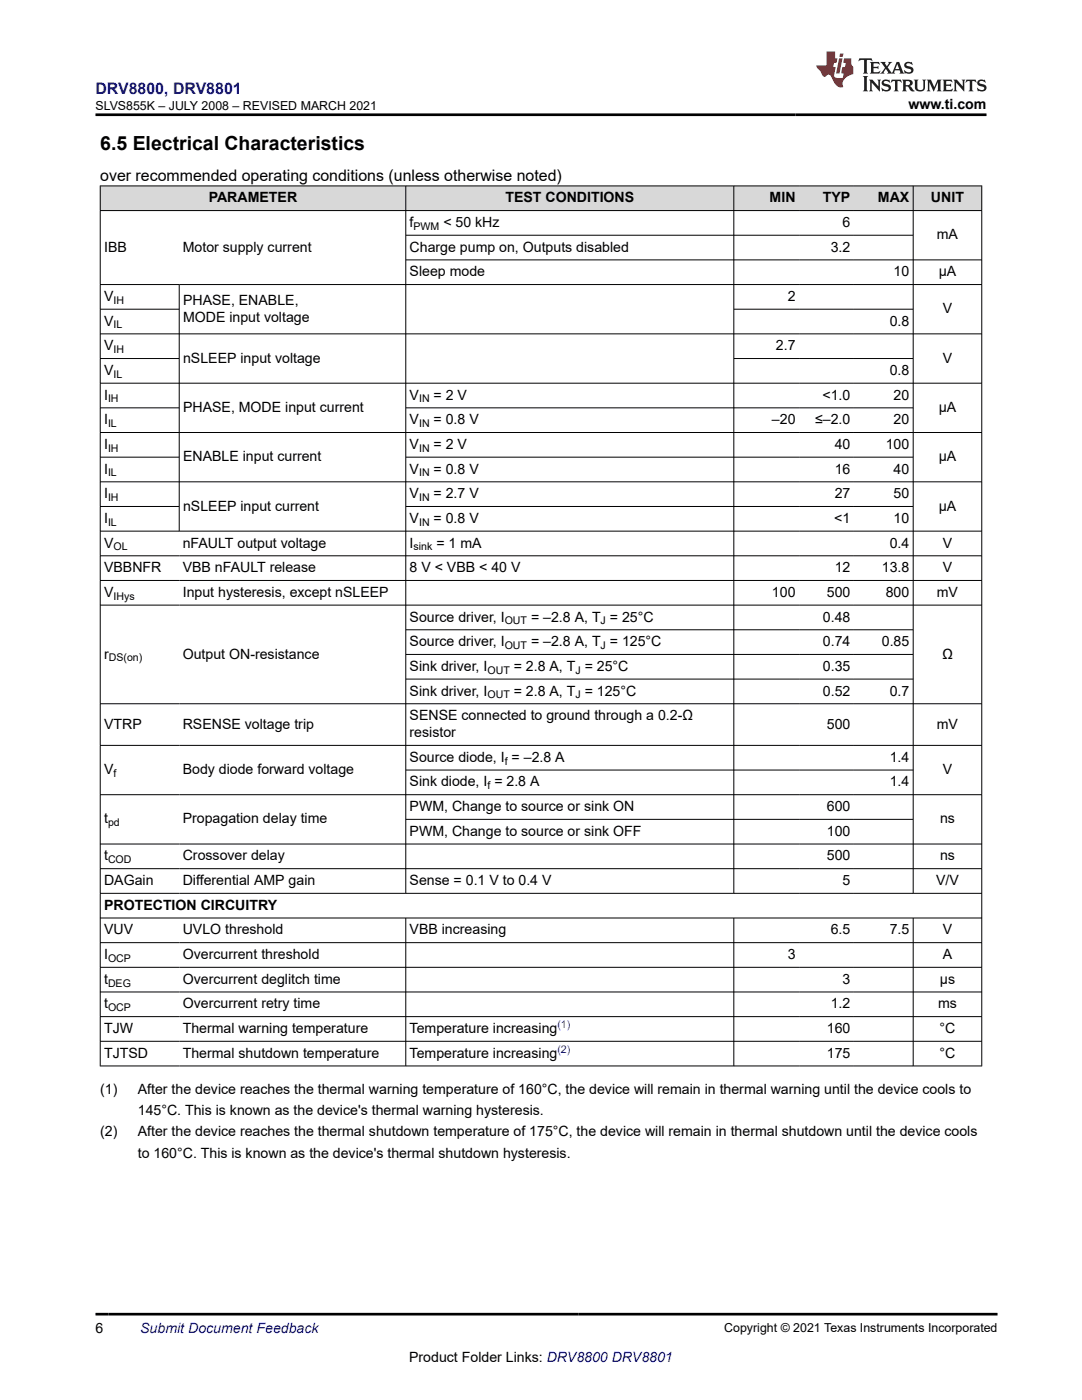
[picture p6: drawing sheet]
<svg xmlns="http://www.w3.org/2000/svg" width="216mm" height="279mm" viewBox="0 0 216 279" stroke-linecap="round" stroke-linejoin="round" font-family="sans-serif">
<defs><g id="words">
<text font-size="3.9" x="20" y="29.9">6.5 Electrical Characteristics</text>
<text font-size="3.2" fill="#00f" x="19.1" y="18.7">DRV8800, DRV8801</text>
<text font-size="3.2" x="20" y="36.1">over recommended operating conditions (unless otherwise noted)</text>
<g font-size="2.8">
<text x="181.3" y="21.8">www.ti.com</text>
<text x="41.7" y="40.4">PARAMETER</text>
<text x="100.8" y="40.4">TEST CONDITIONS</text>
<text x="153.6" y="40.4">MIN</text>
<text x="164.2" y="40.4">TYP</text>
<text x="175.2" y="40.4">MAX</text>
<text x="185.8" y="40.4">UNIT</text>
<text x="81.7" y="45.3">f</text>
<text x="88.5" y="45.3">&lt; 50 kHz</text>
<text x="168.1" y="45.3">6</text>
<text x="186.9" y="47.8">mA</text>
<text x="20.8" y="50.2">IBB</text>
<text x="36.5" y="50.2">Motor supply current</text>
<text x="81.7" y="50.2">Charge pump on, Outputs disabled</text>
<text x="165.8" y="50.2">3.2</text>
<text x="81.7" y="55.1">Sleep mode</text>
<text x="178.3" y="55.1">10</text>
<text x="187.3" y="55.1">μA</text>
<text x="20.8" y="65">V</text>
<text x="20.8" y="60.1">V</text>
<text x="36.5" y="60.8">PHASE, ENABLE,</text>
<text x="36.5" y="64.2">MODE input voltage</text>
<text x="157.2" y="60.1">2</text>
<text x="177.5" y="65">0.8</text>
<text x="188.1" y="62.5">V</text>
<text x="20.8" y="69.9">V</text>
<text x="154.8" y="69.9">2.7</text>
<text x="20.8" y="74.8">V</text>
<text x="36.5" y="72.4">nSLEEP input voltage</text>
<text x="177.5" y="74.8">0.8</text>
<text x="188.1" y="72.4">V</text>
<text x="20.8" y="79.7">I</text>
<text x="36.5" y="82.2">PHASE, MODE input current</text>
<text x="81.7" y="79.7">V</text>
<text x="86.5" y="79.7">= 2 V</text>
<text x="164.1" y="79.7">&lt;1.0</text>
<text x="178.3" y="79.7">20</text>
<text x="187.3" y="82.2">μA</text>
<text x="20.8" y="84.7">I</text>
<text x="20.8" y="89.6">I</text>
<text x="81.7" y="84.7">V</text>
<text x="81.7" y="89.6">V</text>
<text x="86.5" y="89.6">= 2 V</text>
<text x="86.5" y="84.7">= 0.8 V</text>
<text x="154" y="84.7">–20</text>
<text x="162.6" y="84.7">≤–2.0</text>
<text x="166.6" y="89.6">40</text>
<text x="176.7" y="89.6">100</text>
<text x="178.3" y="84.7">20</text>
<text x="20.8" y="94.5">I</text>
<text x="36.5" y="92.1">ENABLE input current</text>
<text x="81.7" y="94.5">V</text>
<text x="86.5" y="94.5">= 0.8 V</text>
<text x="166.6" y="94.5">16</text>
<text x="178.3" y="94.5">40</text>
<text x="187.3" y="92.1">μA</text>
<text x="20.8" y="99.4">I</text>
<text x="36.5" y="101.9">nSLEEP input current</text>
<text x="81.7" y="99.4">V</text>
<text x="86.5" y="99.4">= 2.7 V</text>
<text x="166.6" y="99.4">27</text>
<text x="178.3" y="99.4">50</text>
<text x="187.3" y="101.9">μA</text>
<text x="20.8" y="104.4">I</text>
<text x="81.7" y="104.4">V</text>
<text x="86.5" y="104.4">= 0.8 V</text>
<text x="166.5" y="104.4">&lt;1</text>
<text x="178.3" y="104.4">10</text>
<text x="20.8" y="109.3">V</text>
<text x="36.5" y="109.3">nFAULT output voltage</text>
<text x="81.7" y="109.3">I</text>
<text x="87.1" y="109.3">= 1 mA</text>
<text x="177.5" y="109.3">0.4</text>
<text x="188.1" y="109.3">V</text>
<text x="20.8" y="114.2">VBBNFR</text>
<text x="20.8" y="119.1">V</text>
<text x="36.5" y="114.2">VBB nFAULT release</text>
<text x="36.5" y="119.1">Input hysteresis, except nSLEEP</text>
<text x="81.7" y="114.2">8 V &lt; VBB &lt; 40 V</text>
<text x="154" y="119.1">100</text>
<text x="165" y="119.1">500</text>
<text x="166.6" y="114.2">12</text>
<text x="176" y="114.2">13.8</text>
<text x="176.7" y="119.1">800</text>
<text x="186.9" y="119.1">mV</text>
<text x="188.1" y="114.2">V</text>
<text x="81.7" y="124">Source driver, I</text>
<text x="106" y="124">= –2.8 A, T = 25°C</text>
<text x="164.2" y="124">0.48</text>
<text x="20.8" y="131.4">r</text>
<text x="36.5" y="131.4">Output ON-resistance</text>
<text x="81.7" y="129">Source driver, I</text>
<text x="106" y="129">= –2.8 A, T = 125°C</text>
<text x="164.2" y="129">0.74</text>
<text x="176" y="129">0.85</text>
<text x="188" y="131.4">Ω</text>
<text x="81.7" y="133.9">Sink driver, I</text>
<text x="102.5" y="133.9">= 2.8 A, T = 25°C</text>
<text x="164.2" y="133.9">0.35</text>
<text x="81.7" y="138.8">Sink driver, I</text>
<text x="81.7" y="143.7">SENSE connected to ground through a 0.2-Ω</text>
<text x="102.5" y="138.8">= 2.8 A, T = 125°C</text>
<text x="164.2" y="138.8">0.52</text>
<text x="177.5" y="138.8">0.7</text>
<text x="20.8" y="145.4">VTRP</text>
<text x="36.5" y="145.4">RSENSE voltage trip</text>
<text x="81.7" y="147.1">resistor</text>
<text x="165" y="145.4">500</text>
<text x="186.9" y="145.4">mV</text>
<text x="20.8" y="154.5">V</text>
<text x="36.5" y="154.5">Body diode forward voltage</text>
<text x="81.7" y="152">Source diode, I = –2.8 A</text>
<text x="177.5" y="152">1.4</text>
<text x="188.1" y="154.5">V</text>
<text x="81.7" y="161.9">PWM, Change to source or sink ON</text>
<text x="81.7" y="157">Sink diode, I = 2.8 A</text>
<text x="165" y="161.9">600</text>
<text x="177.5" y="157">1.4</text>
<text x="20.8" y="164.3">t</text>
<text x="36.5" y="164.3">Propagation delay time</text>
<text x="81.7" y="166.8">PWM, Change to source or sink OFF</text>
<text x="165" y="166.8">100</text>
<text x="187.6" y="164.3">ns</text>
<text x="20.8" y="171.7">t</text>
<text x="36.5" y="171.7">Crossover delay</text>
<text x="165" y="171.7">500</text>
<text x="187.6" y="171.7">ns</text>
<text x="20.8" y="176.6">DAGain</text>
<text x="36.5" y="176.6">Differential AMP gain</text>
<text x="81.7" y="176.6">Sense = 0.1 V to 0.4 V</text>
<text x="168.1" y="176.6">5</text>
<text x="186.8" y="176.6">V/V</text>
<text x="20.8" y="181.6">PROTECTION CIRCUITRY</text>
<text x="20.8" y="186.5">VUV</text>
<text x="20.8" y="191.4">I</text>
<text x="36.5" y="186.5">UVLO threshold</text>
<text x="36.5" y="191.4">Overcurrent threshold</text>
<text x="81.7" y="186.5">VBB increasing</text>
<text x="157.2" y="191.4">3</text>
<text x="165.8" y="186.5">6.5</text>
<text x="177.5" y="186.5">7.5</text>
<text x="188.1" y="191.4">A</text>
<text x="188.1" y="186.5">V</text>
<text x="20.8" y="196.3">t</text>
<text x="36.5" y="196.3">Overcurrent deglitch time</text>
<text x="168.1" y="196.3">3</text>
<text x="187.5" y="196.3">µs</text>
<text x="20.8" y="201.2">t</text>
<text x="36.5" y="201.2">Overcurrent retry time</text>
<text x="165.8" y="201.2">1.2</text>
<text x="187.2" y="201.2">ms</text>
<text x="20.8" y="206.2">TJW</text>
<text x="36.5" y="206.2">Thermal warning temperature</text>
<text x="81.7" y="206.2">Temperature increasing</text>
<text x="165" y="206.2">160</text>
<text x="187.5" y="206.2">°C</text>
<text x="20.8" y="211.1">TJTSD</text>
<text x="36.5" y="211.1">Thermal shutdown temperature</text>
<text x="81.7" y="211.1">Temperature increasing</text>
<text x="165" y="211.1">175</text>
<text x="187.5" y="211.1">°C</text>
<text x="20" y="218.3">(1)</text>
<text x="27.5" y="218.3">After the device reaches the thermal warning temperature of 160°C, the device will remain in thermal warning until the device cools to</text>
<text x="20" y="226.8">(2)</text>
<text x="27.5" y="222.5">145°C. This is known as the device's thermal warning hysteresis.</text>
<text x="27.5" y="226.8">After the device reaches the thermal shutdown temperature of 175°C, the device will remain in thermal shutdown until the device cools</text>
<text x="27.5" y="231">to 160°C. This is known as the device's thermal shutdown hysteresis.</text>
<text x="19" y="266.1">6</text>
<text x="81.6" y="271.7">Product Folder Links: DRV8800 DRV8801</text>
</g>
<text font-size="2.8" fill="#00f" x="28" y="266.1">Submit Document Feedback</text>
<g font-size="2.5">
<text x="19" y="21.9">SLVS855K – JULY 2008 – REVISED MARCH 2021</text>
<text x="144.5" y="265.8">Copyright © 2021 Texas Instruments Incorporated</text>
</g>
<g font-size="2.1">
<text x="82.5" y="45.9">PWM</text>
<text x="22.6" y="65.5">IL</text>
<text x="22.6" y="60.6">IH</text>
<text x="22.7" y="70.5">IH</text>
<text x="22.7" y="75.4">IL</text>
<text x="21.6" y="80.3">IH</text>
<text x="83.6" y="80.3">IN</text>
<text x="21.6" y="85.2">IL</text>
<text x="83.6" y="85.2">IN</text>
<text x="21.6" y="90.2">IH</text>
<text x="21.6" y="95.1">IL</text>
<text x="83.6" y="90.2">IN</text>
<text x="83.6" y="95.1">IN</text>
<text x="21.6" y="100">IH</text>
<text x="83.6" y="100">IN</text>
<text x="21.6" y="104.9">IL</text>
<text x="83.6" y="104.9">IN</text>
<text x="22.7" y="109.8">OL</text>
<text x="82.5" y="109.8">sink</text>
<text x="22.7" y="119.7">IHys</text>
<text x="100.7" y="124.6">OUT</text>
<text x="119.9" y="124.6">J</text>
<text x="21.7" y="132">DS(on)</text>
<text x="100.7" y="129.5">OUT</text>
<text x="119.9" y="129.5">J</text>
<text x="97.3" y="134.4">OUT</text>
<text x="114.8" y="134.4">J</text>
<text x="97.3" y="139.4">OUT</text>
<text x="114.8" y="139.4">J</text>
<text x="22.7" y="155.1">f</text>
<text x="100.7" y="152.6">f</text>
<text x="97.3" y="157.5">f</text>
<text x="21.6" y="164.9">pd</text>
<text x="21.6" y="172.3">COD</text>
<text x="21.6" y="192">OCP</text>
<text x="21.6" y="196.9">DEG</text>
<text x="21.6" y="201.8">OCP</text>
</g>
<g font-size="2.1" fill="#00f">
<text x="111.2" y="205.2">(1)</text>
<text x="111.2" y="210.1">(2)</text>
</g>
</g></defs>
<g fill="#d8d8d8">
<path d="M20 37.1h175.9v4.9h-175.9z" fill-rule="evenodd"/>
<path d="M20.1 37.2h60.8v4.8h-60.8z" fill-rule="evenodd"/>
<path d="M81 37.2h65.4v4.8h-65.4z" fill-rule="evenodd"/>
<path d="M146.5 37.2h13v4.8h-13z" fill-rule="evenodd"/>
<path d="M159.5 37.2h10.9v4.8h-10.9z" fill-rule="evenodd"/>
<path d="M170.4 37.2h11.8v4.8h-11.8z" fill-rule="evenodd"/>
<path d="M182.3 37.2h13.5v4.8h-13.5z" fill-rule="evenodd"/>
</g>
<g fill="none" stroke="#000" stroke-width=".2">
<path d="M19.9 37.1h176.1M20 37v175.8M81 37v141.3M146.4 37v141.3M182.2 37v141.3M195.9 37v175.8M19.9 42h176.1M19.9 56.8h176.1M35.8 56.8v49.3M81 46.9h101.3M196 51.9h-115M19.9 61.7h15.9"/>
<path d="M19.9 71.6h15.9M146.4 61.7h35.9M146.4 71.6h35.9M196 66.6h-176.1M196 76.5h-176.1M19.9 81.4h15.9M19.9 91.2h15.9M81 81.4h101.3M81 91.2h101.3M196 86.3h-176.1M196 96.2h-176.1M19.9 101.1h15.9"/>
<path d="M19.9 106h176.1M19.9 110.9h176.1M19.9 115.8h176.1M81 101.1h101.3M19.9 120.8h176.1M81 125.7h101.3M81 130.6h101.3M81 135.5h101.3M19.9 140.4h176.1M19.9 148.8h176.1M19.9 158.6h176.1M81 153.7h101.3"/>
<path d="M19.9 168.4h176.1M19.9 173.4h176.1M19.9 178.3h176.1M81 163.5h101.3M19.9 183.2h176.1M19.9 188.1h176.1M19.9 193h176.1M19.9 198h176.1M81 183.2v29.6M146.4 183.2v29.6M182.2 183.2v29.6M19.9 202.9h176.1"/>
<path d="M19.9 207.8h176.1M19.9 212.7h176.1"/>
</g>
<path d="M171.5 11.6l-.2 .6 .5-.2h.6v.1v2.2l-.2 .4h1l-.2-.4v-2.2v-.1h.5l.6 .2-.2-.6zM173.6 12.4l.2 .3v1.6l-.2 .4h1.9l.1-.6a1.08 1.08 0 0 1-1.3 .2v-.7h.6l.4 .2v-.7l-.4 .2h-.6v-.5l.2-.2a1 1 0 0 1 1 .3l-.1-.5zM175.7 12.4l.9 1.1-1 1.2h.9l-.2-.2 .5-.8 .4 .8-.2 .2h1.6l-.2-.2 .2-.5h.9l.1 .5-.1 .2h.9l-.2-.4-.8-1.9h-.5l-.9 2.1-.9-1.1 .9-1h-.8l.2 .2-.4 .6-.4-.6 .2-.2zM179 12.8l.4 1h-.7zM180.7 12.5a.65 .65 0 0 0-.2 .7 .65 .65 0 0 0 .6 .5l.6 .1 .1 .3a.79 .79 0 0 1-.7 .4 .79 .79 0 0 1-.7-.5l.1 .7 .2-.1a.93 .93 0 0 0 1.1 0 .93 .93 0 0 0 .4-.9 1.46 1.46 0 0 0-1.2-.6l-.1-.3a1.09 1.09 0 0 1 1.2 .2l-.2-.6-.1 .1-.5-.2zM172.2 15.2l.2 .4v2.2l-.2 .4h1l-.2-.4v-2.2l.2-.4zM173.4 15.9l.2 .4v1.5l-.2 .4h.8l-.3-.4 .1-1.3 1.6 1.8v-2l.2-.4h-.7l.1 .2 .1 1.1-1.2-1.3zM176.2 16a.65 .65 0 0 0-.2 .8 .65 .65 0 0 0 .6 .4l.6 .2 .1 .2a.79 .79 0 0 1-.7 .4 .79 .79 0 0 1-.7-.5l.1 .7 .2-.1a.93 .93 0 0 0 1.1 .1 .93 .93 0 0 0 .4-1 1.46 1.46 0 0 0-1.2-.5l-.1-.4a1.09 1.09 0 0 1 1.2 .2l-.1-.6-.2 .1-.5-.1zM177.9 15.9l-.1 .6a.63 .63 0 0 1 .8-.3v1.6l-.3 .4h1l-.2-.4v-1.6a.66 .66 0 0 1 .8 .3l-.1-.6zM180 15.9l.2 .4v1.5l-.2 .4h1l-.2-.2-.1-.7h.5l.1 .2a.79 .79 0 0 0 1.2 .6l-1-.9a.61 .61 0 0 0 .6-.6 .61 .61 0 0 0-.5-.7zM180.8 16.2h.1a.47 .47 0 0 1 .5 .1 .47 .47 0 0 1 .1 .5l-.1 .1-.7 .1zM182.3 15.9l.2 .2a2.27 2.27 0 0 0 .4 2 1.04 1.04 0 0 0 1.7-.7v-1.3l.2-.2h-.8l.2 .4v1.1a.6 .6 0 0 1-.6 .6 .6 .6 0 0 1-.6-.6v-1.1l.3-.4zM184.9 15.9l.2 .4v1.5l-.2 .4h.8l-.3-.4v-1.4l.9 1.9 .9-1.9v1.4l-.3 .4h1l-.2-.4v-1.5l.2-.4h-.8l-.7 1.5-.6-1.5zM188.1 15.9l.2 .4v1.5l-.2 .4h1.9l.1-.6a1.09 1.09 0 0 1-1.3 .2v-.7h.6l.4 .2v-.6l-.4 .2h-.6v-.6l.2-.1a1.01 1.01 0 0 1 1 .3l-.1-.6zM190.2 15.9l.3 .4v1.5l-.3 .4h.8l-.2-.4v-1.3l1.6 1.8v-2l.2-.4h-.7l.2 .2v1.1l-1.2-1.3zM192.8 15.9l-.1 .6a.63 .63 0 0 1 .8-.3v1.6l-.3 .4h1l-.2-.4v-1.6a.66 .66 0 0 1 .8 .3l-.1-.6zM195.2 16a.65 .65 0 0 0-.2 .8 .65 .65 0 0 0 .6 .4l.6 .2 .2 .2a.79 .79 0 0 1-.7 .4 .79 .79 0 0 1-.7-.5l.1 .7 .2-.1a.93 .93 0 0 0 1 .1 .93 .93 0 0 0 .5-1 1.46 1.46 0 0 0-1.3-.5v-.4a1.09 1.09 0 0 1 1.2 .2l-.2-.6-.2 .1-.5-.1z" fill="#231f20"/>
<path d="M164.9 10.3v2.7h-2l.1 .4 .8 1a.95 .95 0 0 0 1 .9 .59 .59 0 0 1 .5-.4 .59 .59 0 0 1 .5 .3l.4 .8a1.59 1.59 0 0 0 2.1 1.4 1.61 1.61 0 0 1 1-2.3l1-.3-.1-1.5a1.59 1.59 0 0 1-.3-1.7h-1.5l-.2 .9h.6l-.2 .9h-.5l-.2 .9v.3l.4 .1-.1 .9h-.7a.73 .73 0 0 1-1-.7l.3-1.5h-.5l.1-.9h.5l.2-.9h-.5v-1.3zM167.4 11.6l-.6 3.1h.7l.6-3.1zM167.6 10.7l-.1 .6h.7l.1-.6z" fill="#ed1c24"/>
<path d="M19 22.9h177.8M19 262.3h180" fill="none" stroke="#000" stroke-width=".53"/>
<use href="#words"/>
</svg>
